One B-rep face of a CAD part: STEP entity #338.
In plain terms, the planar face has unit normal (0, 0, 1).
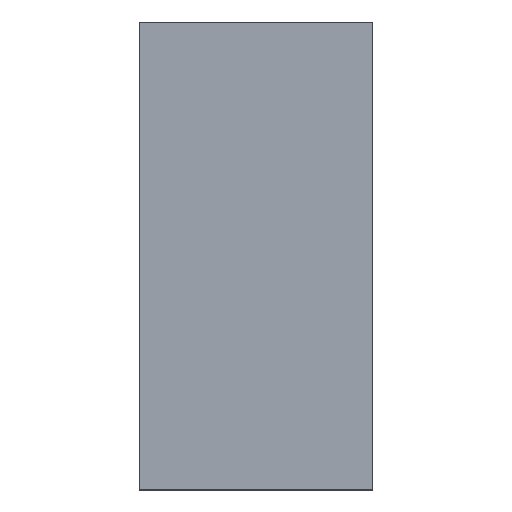
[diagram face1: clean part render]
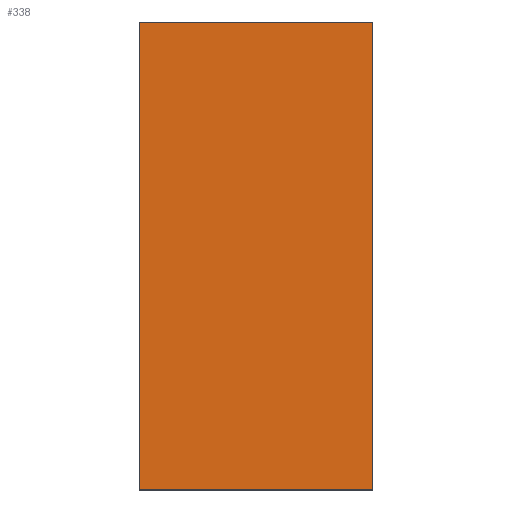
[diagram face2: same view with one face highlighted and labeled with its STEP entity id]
Its self-contained STEP definition (entity closure, numbers rounded to 3 decimals):
#24 = VERTEX_POINT('',#25);
#25 = CARTESIAN_POINT('',(-75.,-150.,12.));
#32 = PLANE('',#33);
#33 = AXIS2_PLACEMENT_3D('',#34,#35,#36);
#34 = CARTESIAN_POINT('',(-75.,-150.,0.));
#35 = DIRECTION('',(0.,1.,0.));
#36 = DIRECTION('',(1.,0.,0.));
#44 = PLANE('',#45);
#45 = AXIS2_PLACEMENT_3D('',#46,#47,#48);
#46 = CARTESIAN_POINT('',(-75.,150.,0.));
#47 = DIRECTION('',(1.,0.,-0.));
#48 = DIRECTION('',(0.,-1.,0.));
#56 = EDGE_CURVE('',#24,#57,#59,.T.);
#57 = VERTEX_POINT('',#58);
#58 = CARTESIAN_POINT('',(75.,-150.,12.));
#59 = SURFACE_CURVE('',#60,(#64,#71),.PCURVE_S1.);
#60 = LINE('',#61,#62);
#61 = CARTESIAN_POINT('',(-75.,-150.,12.));
#62 = VECTOR('',#63,1.);
#63 = DIRECTION('',(1.,0.,0.));
#64 = PCURVE('',#32,#65);
#65 = DEFINITIONAL_REPRESENTATION('',(#66),#70);
#66 = LINE('',#67,#68);
#67 = CARTESIAN_POINT('',(0.,-12.));
#68 = VECTOR('',#69,1.);
#69 = DIRECTION('',(1.,0.));
#70 = ( GEOMETRIC_REPRESENTATION_CONTEXT(2) 
PARAMETRIC_REPRESENTATION_CONTEXT() REPRESENTATION_CONTEXT('2D SPACE',''
  ) );
#71 = PCURVE('',#72,#77);
#72 = PLANE('',#73);
#73 = AXIS2_PLACEMENT_3D('',#74,#75,#76);
#74 = CARTESIAN_POINT('',(0.,0.,12.));
#75 = DIRECTION('',(0.,0.,1.));
#76 = DIRECTION('',(1.,0.,-0.));
#77 = DEFINITIONAL_REPRESENTATION('',(#78),#82);
#78 = LINE('',#79,#80);
#79 = CARTESIAN_POINT('',(-75.,-150.));
#80 = VECTOR('',#81,1.);
#81 = DIRECTION('',(1.,0.));
#82 = ( GEOMETRIC_REPRESENTATION_CONTEXT(2) 
PARAMETRIC_REPRESENTATION_CONTEXT() REPRESENTATION_CONTEXT('2D SPACE',''
  ) );
#100 = PLANE('',#101);
#101 = AXIS2_PLACEMENT_3D('',#102,#103,#104);
#102 = CARTESIAN_POINT('',(75.,-150.,0.));
#103 = DIRECTION('',(-1.,0.,0.));
#104 = DIRECTION('',(0.,1.,0.));
#142 = EDGE_CURVE('',#57,#143,#145,.T.);
#143 = VERTEX_POINT('',#144);
#144 = CARTESIAN_POINT('',(75.,150.,12.));
#145 = SURFACE_CURVE('',#146,(#150,#157),.PCURVE_S1.);
#146 = LINE('',#147,#148);
#147 = CARTESIAN_POINT('',(75.,-150.,12.));
#148 = VECTOR('',#149,1.);
#149 = DIRECTION('',(0.,1.,0.));
#150 = PCURVE('',#100,#151);
#151 = DEFINITIONAL_REPRESENTATION('',(#152),#156);
#152 = LINE('',#153,#154);
#153 = CARTESIAN_POINT('',(0.,-12.));
#154 = VECTOR('',#155,1.);
#155 = DIRECTION('',(1.,0.));
#156 = ( GEOMETRIC_REPRESENTATION_CONTEXT(2) 
PARAMETRIC_REPRESENTATION_CONTEXT() REPRESENTATION_CONTEXT('2D SPACE',''
  ) );
#157 = PCURVE('',#72,#158);
#158 = DEFINITIONAL_REPRESENTATION('',(#159),#163);
#159 = LINE('',#160,#161);
#160 = CARTESIAN_POINT('',(75.,-150.));
#161 = VECTOR('',#162,1.);
#162 = DIRECTION('',(0.,1.));
#163 = ( GEOMETRIC_REPRESENTATION_CONTEXT(2) 
PARAMETRIC_REPRESENTATION_CONTEXT() REPRESENTATION_CONTEXT('2D SPACE',''
  ) );
#181 = PLANE('',#182);
#182 = AXIS2_PLACEMENT_3D('',#183,#184,#185);
#183 = CARTESIAN_POINT('',(75.,150.,0.));
#184 = DIRECTION('',(0.,-1.,0.));
#185 = DIRECTION('',(-1.,0.,0.));
#218 = EDGE_CURVE('',#143,#219,#221,.T.);
#219 = VERTEX_POINT('',#220);
#220 = CARTESIAN_POINT('',(-75.,150.,12.));
#221 = SURFACE_CURVE('',#222,(#226,#233),.PCURVE_S1.);
#222 = LINE('',#223,#224);
#223 = CARTESIAN_POINT('',(75.,150.,12.));
#224 = VECTOR('',#225,1.);
#225 = DIRECTION('',(-1.,0.,0.));
#226 = PCURVE('',#181,#227);
#227 = DEFINITIONAL_REPRESENTATION('',(#228),#232);
#228 = LINE('',#229,#230);
#229 = CARTESIAN_POINT('',(0.,-12.));
#230 = VECTOR('',#231,1.);
#231 = DIRECTION('',(1.,0.));
#232 = ( GEOMETRIC_REPRESENTATION_CONTEXT(2) 
PARAMETRIC_REPRESENTATION_CONTEXT() REPRESENTATION_CONTEXT('2D SPACE',''
  ) );
#233 = PCURVE('',#72,#234);
#234 = DEFINITIONAL_REPRESENTATION('',(#235),#239);
#235 = LINE('',#236,#237);
#236 = CARTESIAN_POINT('',(75.,150.));
#237 = VECTOR('',#238,1.);
#238 = DIRECTION('',(-1.,0.));
#239 = ( GEOMETRIC_REPRESENTATION_CONTEXT(2) 
PARAMETRIC_REPRESENTATION_CONTEXT() REPRESENTATION_CONTEXT('2D SPACE',''
  ) );
#289 = EDGE_CURVE('',#219,#24,#290,.T.);
#290 = SURFACE_CURVE('',#291,(#295,#302),.PCURVE_S1.);
#291 = LINE('',#292,#293);
#292 = CARTESIAN_POINT('',(-75.,150.,12.));
#293 = VECTOR('',#294,1.);
#294 = DIRECTION('',(0.,-1.,0.));
#295 = PCURVE('',#44,#296);
#296 = DEFINITIONAL_REPRESENTATION('',(#297),#301);
#297 = LINE('',#298,#299);
#298 = CARTESIAN_POINT('',(0.,-12.));
#299 = VECTOR('',#300,1.);
#300 = DIRECTION('',(1.,0.));
#301 = ( GEOMETRIC_REPRESENTATION_CONTEXT(2) 
PARAMETRIC_REPRESENTATION_CONTEXT() REPRESENTATION_CONTEXT('2D SPACE',''
  ) );
#302 = PCURVE('',#72,#303);
#303 = DEFINITIONAL_REPRESENTATION('',(#304),#308);
#304 = LINE('',#305,#306);
#305 = CARTESIAN_POINT('',(-75.,150.));
#306 = VECTOR('',#307,1.);
#307 = DIRECTION('',(0.,-1.));
#308 = ( GEOMETRIC_REPRESENTATION_CONTEXT(2) 
PARAMETRIC_REPRESENTATION_CONTEXT() REPRESENTATION_CONTEXT('2D SPACE',''
  ) );
#338 = ADVANCED_FACE('',(#339),#72,.T.);
#339 = FACE_BOUND('',#340,.T.);
#340 = EDGE_LOOP('',(#341,#342,#343,#344));
#341 = ORIENTED_EDGE('',*,*,#56,.T.);
#342 = ORIENTED_EDGE('',*,*,#142,.T.);
#343 = ORIENTED_EDGE('',*,*,#218,.T.);
#344 = ORIENTED_EDGE('',*,*,#289,.T.);
